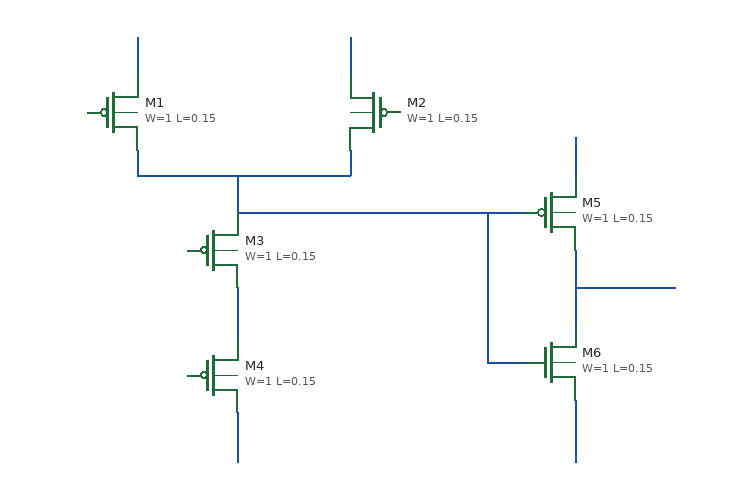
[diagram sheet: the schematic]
v {xschem version=3.0.0 file_version=1.2 }
G {}
K {}
V {}
S {}
E {}
N 60 -20 60 0 {
lab=#net1}
N 60 0 230 -0 {
lab=#net1}
N 230 -20 230 -0 {
lab=#net1}
N 140 -0 140 30 {
lab=#net1}
N 140 90 140 130 {
lab=#net2}
N 140 30 370 30 {
lab=#net1}
N 340 30 340 150 {
lab=#net1}
N 340 150 370 150 {
lab=#net1}
N 410 60 410 120 {
lab=#net3}
N 410 90 490 90 {
lab=#net3}
N 60 -110 60 -80 {
lab=#net4}
N 230 -110 230 -80 {
lab=#net5}
N 410 -30 410 0 {
lab=#net6}
N 140 190 140 230 {
lab=#net7}
N 410 180 410 230 {
lab=GND}
C {sky130_fd_pr/pfet_01v8.sym} 40 -50 0 0 {name=M1
L=0.15
W=1
nf=1
mult=1
ad="'int((nf+1)/2) * W/nf * 0.29'" 
pd="'2*int((nf+1)/2) * (W/nf + 0.29)'"
as="'int((nf+2)/2) * W/nf * 0.29'" 
ps="'2*int((nf+2)/2) * (W/nf + 0.29)'"
nrd="'0.29 / W'" nrs="'0.29 / W'"
sa=0 sb=0 sd=0
model=pfet_01v8
spiceprefix=X
}
C {sky130_fd_pr/pfet_01v8.sym} 250 -50 0 1 {name=M2
L=0.15
W=1
nf=1
mult=1
ad="'int((nf+1)/2) * W/nf * 0.29'" 
pd="'2*int((nf+1)/2) * (W/nf + 0.29)'"
as="'int((nf+2)/2) * W/nf * 0.29'" 
ps="'2*int((nf+2)/2) * (W/nf + 0.29)'"
nrd="'0.29 / W'" nrs="'0.29 / W'"
sa=0 sb=0 sd=0
model=pfet_01v8
spiceprefix=X
}
C {sky130_fd_pr/pfet_01v8.sym} 120 60 0 0 {name=M3
L=0.15
W=1
nf=1
mult=1
ad="'int((nf+1)/2) * W/nf * 0.29'" 
pd="'2*int((nf+1)/2) * (W/nf + 0.29)'"
as="'int((nf+2)/2) * W/nf * 0.29'" 
ps="'2*int((nf+2)/2) * (W/nf + 0.29)'"
nrd="'0.29 / W'" nrs="'0.29 / W'"
sa=0 sb=0 sd=0
model=pfet_01v8
spiceprefix=X
}
C {sky130_fd_pr/pfet_01v8.sym} 120 160 0 0 {name=M4
L=0.15
W=1
nf=1
mult=1
ad="'int((nf+1)/2) * W/nf * 0.29'" 
pd="'2*int((nf+1)/2) * (W/nf + 0.29)'"
as="'int((nf+2)/2) * W/nf * 0.29'" 
ps="'2*int((nf+2)/2) * (W/nf + 0.29)'"
nrd="'0.29 / W'" nrs="'0.29 / W'"
sa=0 sb=0 sd=0
model=pfet_01v8
spiceprefix=X
}
C {sky130_fd_pr/pfet_01v8.sym} 390 30 0 0 {name=M5
L=0.15
W=1
nf=1
mult=1
ad="'int((nf+1)/2) * W/nf * 0.29'" 
pd="'2*int((nf+1)/2) * (W/nf + 0.29)'"
as="'int((nf+2)/2) * W/nf * 0.29'" 
ps="'2*int((nf+2)/2) * (W/nf + 0.29)'"
nrd="'0.29 / W'" nrs="'0.29 / W'"
sa=0 sb=0 sd=0
model=pfet_01v8
spiceprefix=X
}
C {sky130_fd_pr/nfet_01v8.sym} 390 150 0 0 {name=M6
L=0.15
W=1
nf=1 
mult=1
ad="'int((nf+1)/2) * W/nf * 0.29'" 
pd="'2*int((nf+1)/2) * (W/nf + 0.29)'"
as="'int((nf+2)/2) * W/nf * 0.29'" 
ps="'2*int((nf+2)/2) * (W/nf + 0.29)'"
nrd="'0.29 / W'" nrs="'0.29 / W'"
sa=0 sb=0 sd=0
model=nfet_01v8
spiceprefix=X
}
